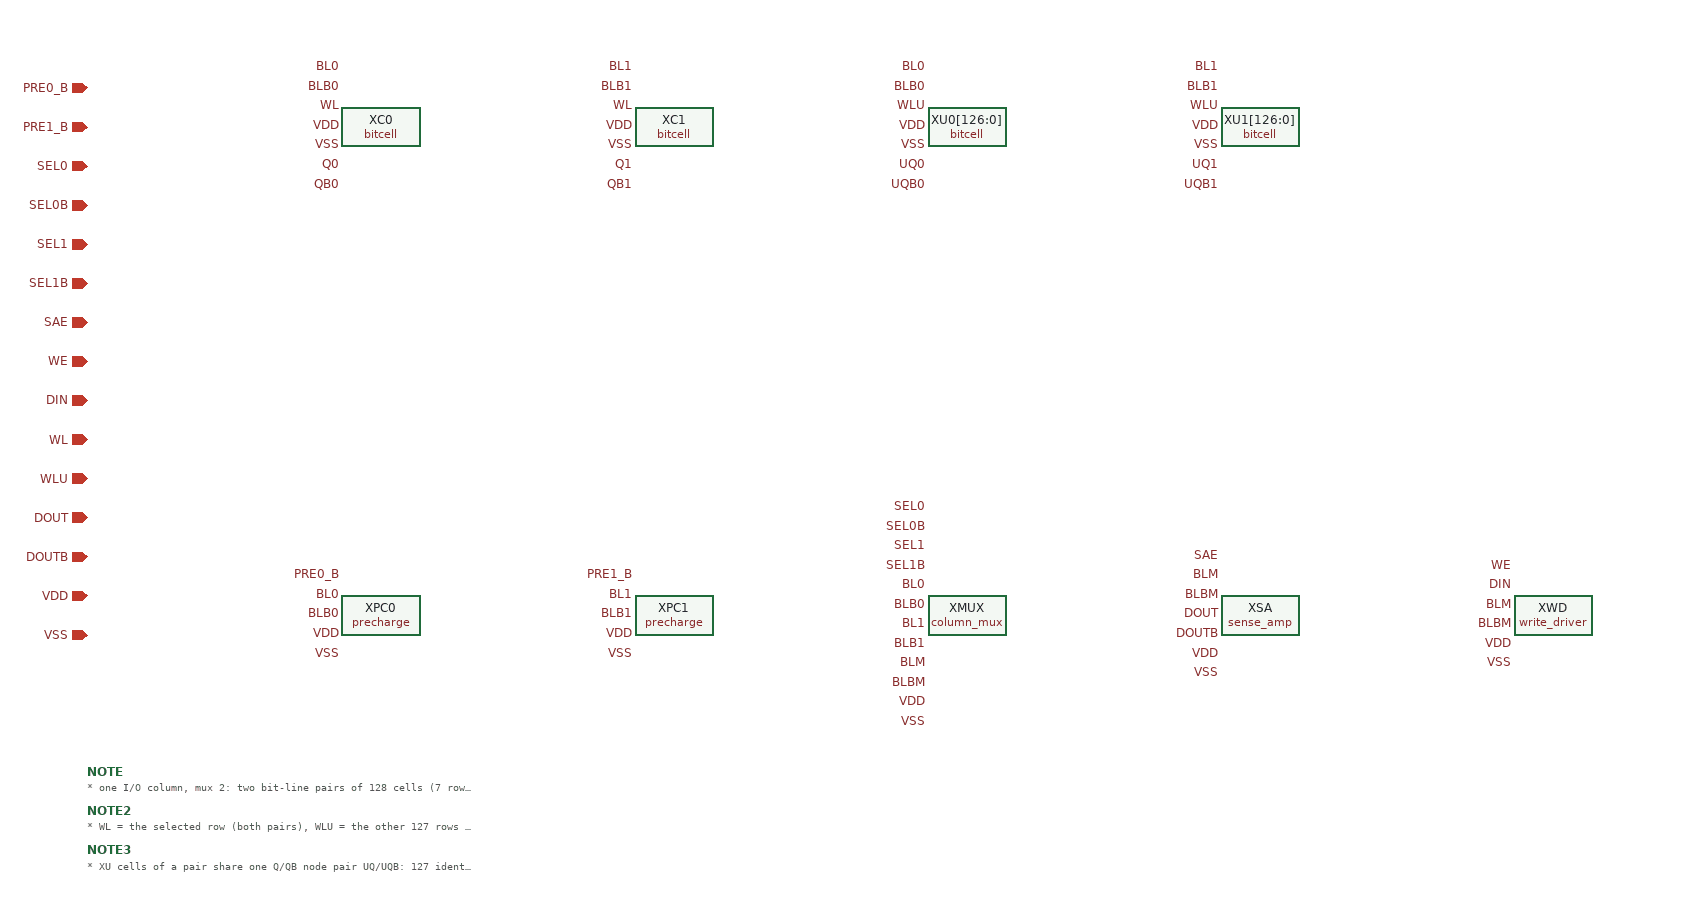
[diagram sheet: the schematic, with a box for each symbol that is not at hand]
v {xschem version=3.4.8RC file_version=1.3}
G {}
K {}
V {}
S {}
E {}
C {../bitcell/bitcell.sym} -600 -300 0 0 {name=XC0}
C {devices/lab_pin.sym} -640 -360 0 0 {name=l0 lab=BL0}
C {devices/lab_pin.sym} -640 -340 0 0 {name=l1 lab=BLB0}
C {devices/lab_pin.sym} -640 -320 0 0 {name=l2 lab=WL}
C {devices/lab_pin.sym} -640 -300 0 0 {name=l3 lab=VDD}
C {devices/lab_pin.sym} -640 -280 0 0 {name=l4 lab=VSS}
C {devices/lab_pin.sym} -640 -260 0 0 {name=l5 lab=Q0}
C {devices/lab_pin.sym} -640 -240 0 0 {name=l6 lab=QB0}
C {../bitcell/bitcell.sym} -300 -300 0 0 {name=XC1}
C {devices/lab_pin.sym} -340 -360 0 0 {name=l7 lab=BL1}
C {devices/lab_pin.sym} -340 -340 0 0 {name=l8 lab=BLB1}
C {devices/lab_pin.sym} -340 -320 0 0 {name=l9 lab=WL}
C {devices/lab_pin.sym} -340 -300 0 0 {name=l10 lab=VDD}
C {devices/lab_pin.sym} -340 -280 0 0 {name=l11 lab=VSS}
C {devices/lab_pin.sym} -340 -260 0 0 {name=l12 lab=Q1}
C {devices/lab_pin.sym} -340 -240 0 0 {name=l13 lab=QB1}
C {../bitcell/bitcell.sym} 0 -300 0 0 {name=XU0[126:0]}
C {devices/lab_pin.sym} -40 -360 0 0 {name=l14 lab=BL0}
C {devices/lab_pin.sym} -40 -340 0 0 {name=l15 lab=BLB0}
C {devices/lab_pin.sym} -40 -320 0 0 {name=l16 lab=WLU}
C {devices/lab_pin.sym} -40 -300 0 0 {name=l17 lab=VDD}
C {devices/lab_pin.sym} -40 -280 0 0 {name=l18 lab=VSS}
C {devices/lab_pin.sym} -40 -260 0 0 {name=l19 lab=UQ0}
C {devices/lab_pin.sym} -40 -240 0 0 {name=l20 lab=UQB0}
C {../bitcell/bitcell.sym} 300 -300 0 0 {name=XU1[126:0]}
C {devices/lab_pin.sym} 260 -360 0 0 {name=l21 lab=BL1}
C {devices/lab_pin.sym} 260 -340 0 0 {name=l22 lab=BLB1}
C {devices/lab_pin.sym} 260 -320 0 0 {name=l23 lab=WLU}
C {devices/lab_pin.sym} 260 -300 0 0 {name=l24 lab=VDD}
C {devices/lab_pin.sym} 260 -280 0 0 {name=l25 lab=VSS}
C {devices/lab_pin.sym} 260 -260 0 0 {name=l26 lab=UQ1}
C {devices/lab_pin.sym} 260 -240 0 0 {name=l27 lab=UQB1}
C {precharge.sym} -600 200 0 0 {name=XPC0}
C {devices/lab_pin.sym} -640 160 0 0 {name=l28 lab=PRE0_B}
C {devices/lab_pin.sym} -640 180 0 0 {name=l29 lab=BL0}
C {devices/lab_pin.sym} -640 200 0 0 {name=l30 lab=BLB0}
C {devices/lab_pin.sym} -640 220 0 0 {name=l31 lab=VDD}
C {devices/lab_pin.sym} -640 240 0 0 {name=l32 lab=VSS}
C {precharge.sym} -300 200 0 0 {name=XPC1}
C {devices/lab_pin.sym} -340 160 0 0 {name=l33 lab=PRE1_B}
C {devices/lab_pin.sym} -340 180 0 0 {name=l34 lab=BL1}
C {devices/lab_pin.sym} -340 200 0 0 {name=l35 lab=BLB1}
C {devices/lab_pin.sym} -340 220 0 0 {name=l36 lab=VDD}
C {devices/lab_pin.sym} -340 240 0 0 {name=l37 lab=VSS}
C {column_mux.sym} 0 200 0 0 {name=XMUX}
C {devices/lab_pin.sym} -40 90 0 0 {name=l38 lab=SEL0}
C {devices/lab_pin.sym} -40 110 0 0 {name=l39 lab=SEL0B}
C {devices/lab_pin.sym} -40 130 0 0 {name=l40 lab=SEL1}
C {devices/lab_pin.sym} -40 150 0 0 {name=l41 lab=SEL1B}
C {devices/lab_pin.sym} -40 170 0 0 {name=l42 lab=BL0}
C {devices/lab_pin.sym} -40 190 0 0 {name=l43 lab=BLB0}
C {devices/lab_pin.sym} -40 210 0 0 {name=l44 lab=BL1}
C {devices/lab_pin.sym} -40 230 0 0 {name=l45 lab=BLB1}
C {devices/lab_pin.sym} -40 250 0 0 {name=l46 lab=BLM}
C {devices/lab_pin.sym} -40 270 0 0 {name=l47 lab=BLBM}
C {devices/lab_pin.sym} -40 290 0 0 {name=l48 lab=VDD}
C {devices/lab_pin.sym} -40 310 0 0 {name=l49 lab=VSS}
C {sense_amp.sym} 300 200 0 0 {name=XSA}
C {devices/lab_pin.sym} 260 140 0 0 {name=l50 lab=SAE}
C {devices/lab_pin.sym} 260 160 0 0 {name=l51 lab=BLM}
C {devices/lab_pin.sym} 260 180 0 0 {name=l52 lab=BLBM}
C {devices/lab_pin.sym} 260 200 0 0 {name=l53 lab=DOUT}
C {devices/lab_pin.sym} 260 220 0 0 {name=l54 lab=DOUTB}
C {devices/lab_pin.sym} 260 240 0 0 {name=l55 lab=VDD}
C {devices/lab_pin.sym} 260 260 0 0 {name=l56 lab=VSS}
C {write_driver.sym} 600 200 0 0 {name=XWD}
C {devices/lab_pin.sym} 560 150 0 0 {name=l57 lab=WE}
C {devices/lab_pin.sym} 560 170 0 0 {name=l58 lab=DIN}
C {devices/lab_pin.sym} 560 190 0 0 {name=l59 lab=BLM}
C {devices/lab_pin.sym} 560 210 0 0 {name=l60 lab=BLBM}
C {devices/lab_pin.sym} 560 230 0 0 {name=l61 lab=VDD}
C {devices/lab_pin.sym} 560 250 0 0 {name=l62 lab=VSS}
C {devices/ipin.sym} -900 -340 0 0 {name=p63 lab=PRE0_B}
C {devices/ipin.sym} -900 -300 0 0 {name=p77 lab=PRE1_B}
C {devices/ipin.sym} -900 -260 0 0 {name=p64 lab=SEL0}
C {devices/ipin.sym} -900 -220 0 0 {name=p65 lab=SEL0B}
C {devices/ipin.sym} -900 -180 0 0 {name=p66 lab=SEL1}
C {devices/ipin.sym} -900 -140 0 0 {name=p67 lab=SEL1B}
C {devices/ipin.sym} -900 -100 0 0 {name=p68 lab=SAE}
C {devices/ipin.sym} -900 -60 0 0 {name=p69 lab=WE}
C {devices/ipin.sym} -900 -20 0 0 {name=p70 lab=DIN}
C {devices/ipin.sym} -900 20 0 0 {name=p71 lab=WL}
C {devices/ipin.sym} -900 60 0 0 {name=p72 lab=WLU}
C {devices/iopin.sym} -900 100 0 0 {name=p73 lab=DOUT}
C {devices/iopin.sym} -900 140 0 0 {name=p74 lab=DOUTB}
C {devices/iopin.sym} -900 180 0 0 {name=p75 lab=VDD}
C {devices/iopin.sym} -900 220 0 0 {name=p76 lab=VSS}
C {devices/code_shown.sym} -900 360 0 0 {name=NOTE only_toplevel=false
place=header
value="* one I/O column, mux 2: two bit-line pairs of 128 cells (7 row + 1 column address bits)."}
C {devices/code_shown.sym} -900 400 0 0 {name=NOTE2 only_toplevel=false
place=header
value="* WL = the selected row (both pairs), WLU = the other 127 rows (shared net, held low)."}
C {devices/code_shown.sym} -900 440 0 0 {name=NOTE3 only_toplevel=false
place=header
value="* XU cells of a pair share one Q/QB node pair UQ/UQB: 127 identical cells, same state."}
